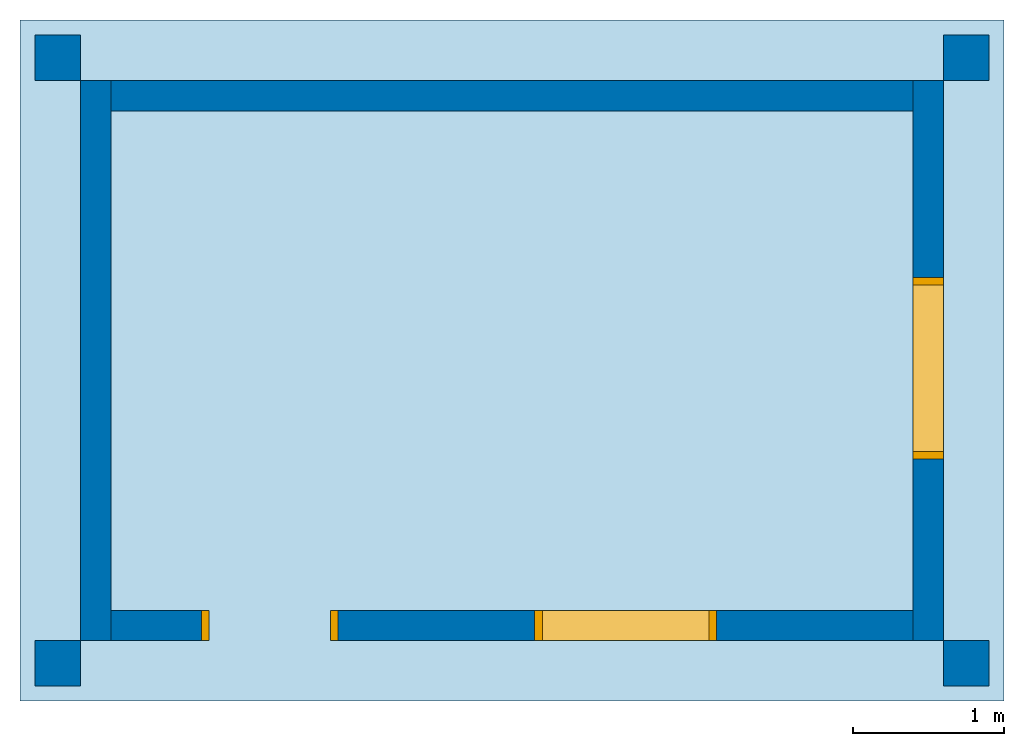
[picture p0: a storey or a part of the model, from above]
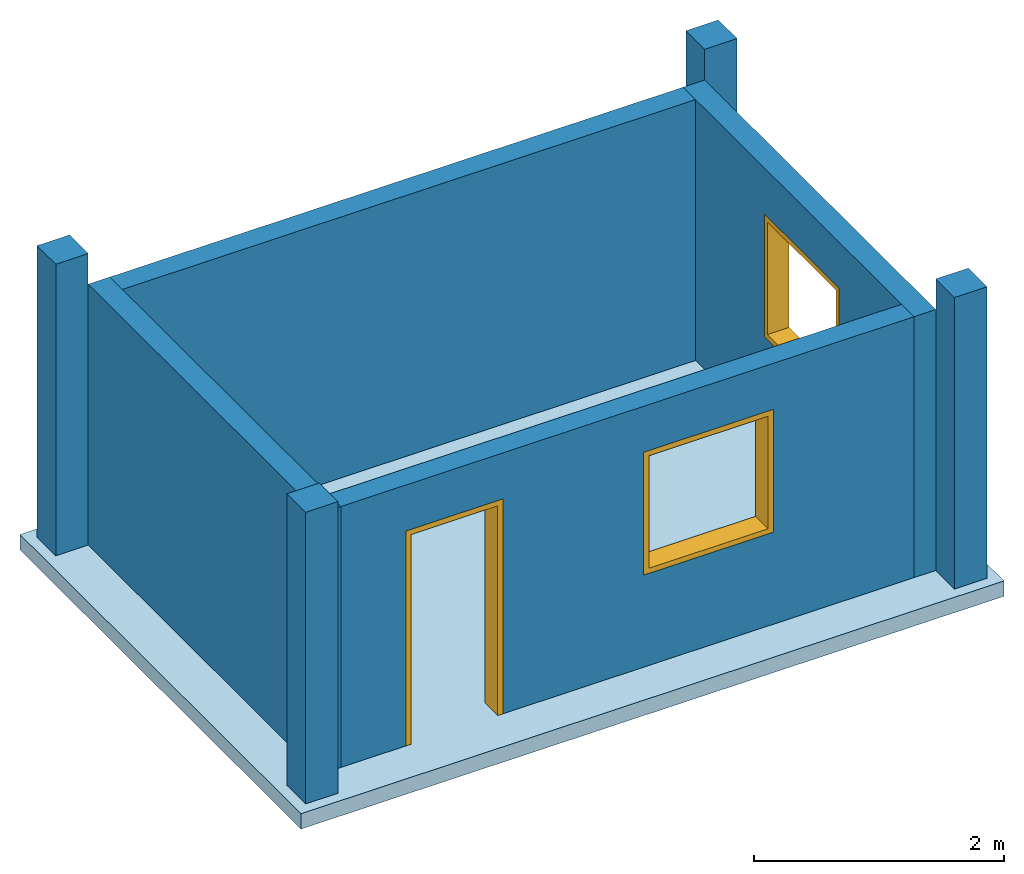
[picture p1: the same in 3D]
Properties of the parts of a building model (IFC4)

# File
Description: 3117 native IFC4 snapshot; declared native building elements and explicit slab-priority joins, Source content revision: b1d7558505e38e8eab14517490e580a875eba1bb7b5503b72d140c259384c804
Time: 2026-10-23T02:40:40
Author: 3117 BIM
Written by: IfcOpenShell 0.8.4
Made in: 3117 BIM Studio 0.5.0

# IfcProject, 3117 อาคารสองชั้น
LongName: BLD-030
BIM3117_Source - ContentRevision: b1d7558505e38e8eab14517490e580a875eba1bb7b5503b72d140c259384c804; NativeObjectName: BIM3117_Project; SourceModel: FreeCAD Document / FCStd; WorkbenchVersion: 0.5.0; ProjectNumber: BLD-030; Author: 3117 BIM; RevisionMeaning: SHA-256 content identity; Undo may restore an earlier identity; QuantityRule: Straight uniform walls, one side; openings deducted; wall joins excluded; CoverageComplete: no

# IfcSite, 3117 Site
BIM3117_Source - ContentRevision: b1d7558505e38e8eab14517490e580a875eba1bb7b5503b72d140c259384c804; Mapping: Generated local site container; no survey/georeferencing claimed

# IfcBuilding, 3117 อาคารสองชั้น
BIM3117_Source - ContentRevision: b1d7558505e38e8eab14517490e580a875eba1bb7b5503b72d140c259384c804; Mapping: Generated building container for the single native Project

# IfcBuildingStorey (3)
In: 3117 อาคารสองชั้น
BIM3117_Source - ContentRevision: b1d7558505e38e8eab14517490e580a875eba1bb7b5503b72d140c259384c804; SourceModel: FreeCAD Document / FCStd; WorkbenchVersion: 0.5.0
Name | Elevation (m) | NativeObjectName
L02 | 6 | BIM3117_Level002
L01 | 3 | BIM3117_Level001
L00 | 0 | BIM3117_Level

# IfcBeam: Beam 300 x 450 (8)
Type - PredefinedType: BEAM; Material: Concrete
Type - BIM3117_Source - ContentRevision: b1d7558505e38e8eab14517490e580a875eba1bb7b5503b72d140c259384c804; NativeObjectName: BIM3117_ElementType002; SourceModel: FreeCAD Document / FCStd; WorkbenchVersion: 0.5.0; TypeCode: B300450; Category: Beam; MaterialLayers: []; WidthM: 0.3; DepthM: 0.45
BIM3117_Source - MaterialDescription: Concrete; JoinRule: Slab takes priority; subtract slab solids from this member only; OffsetM: 0
Qto_BeamBaseQuantities - CrossSectionArea: 0.135 m2
BIM3117_MaterialSource - ContentRevision: b1d7558505e38e8eab14517490e580a875eba1bb7b5503b72d140c259384c804; QuantityRule: 3117.material.native-solid-partition.v1
Name | In | NativeObjectName | JoinDeductionM3 = HomogeneousDeductionVolume (m3) | TopZM | GrossVolume (m3) = HomogeneousGrossVolume (m3) | NetVolume (m3) = HomogeneousNetVolume (m3) | Length (m) | Rows
B12 | L01 | BIM3117_Beam001 | 0.18 | 3 | 0.54 | 0.36 | 4 | [{"category":"Beam","content_revision":"b1d7558505e38e8eab14517490e580a875eba1bb7b5503b72d140c259384c804","deduction_rule":"slab-priority joins","deduction_volume_m3":0.18000000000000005,"element_id":"06e74d45-1fd5-431b-89b8-6fac21c4a78d","gross_volume_m3":0.54,"layer_index":0,"layer_role":"homogeneous","level":"L01","level_id":"3087830e-4d1a-4f80-b674-777b13466c13","material_code":"CONC","material_id":"c914a542-3e86-48de-8977-109cd4dfb8d9","material_name":"Concrete","name":"B12","net_volume_m3":0.36,"object_name":"BIM3117_Beam001","quantity_rule":"3117.material.native-solid-partition.v1","thickness_m":"","type_id":"7873a6d0-4f02-4dc2-a0b7-e65b0801dee5","type_name":"Beam 300 x 450"}]
B21 | L02 | BIM3117_Beam004 | 0.27 | 6 | 0.81 | 0.54 | 6 | [{"category":"Beam","content_revision":"b1d7558505e38e8eab14517490e580a875eba1bb7b5503b72d140c259384c804","deduction_rule":"slab-priority joins","deduction_volume_m3":0.27,"element_id":"0f2f9d10-3b11-4f27-bb93-bc6f454e6b0c","gross_volume_m3":0.81,"layer_index":0,"layer_role":"homogeneous","level":"L02","level_id":"23a017fd-103e-4f8e-bfd1-538f44a944cd","material_code":"CONC","material_id":"c914a542-3e86-48de-8977-109cd4dfb8d9","material_name":"Concrete","name":"B21","net_volume_m3":0.54,"object_name":"BIM3117_Beam004","quantity_rule":"3117.material.native-solid-partition.v1","thickness_m":"","type_id":"7873a6d0-4f02-4dc2-a0b7-e65b0801dee5","type_name":"Beam 300 x 450"}]
B24 | L02 | BIM3117_Beam007 | 0.18 | 6 | 0.54 | 0.36 | 4 | [{"category":"Beam","content_revision":"b1d7558505e38e8eab14517490e580a875eba1bb7b5503b72d140c259384c804","deduction_rule":"slab-priority joins","deduction_volume_m3":0.18000000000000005,"element_id":"37134a20-b003-48ef-96bd-b1457cc94324","gross_volume_m3":0.54,"layer_index":0,"layer_role":"homogeneous","level":"L02","level_id":"23a017fd-103e-4f8e-bfd1-538f44a944cd","material_code":"CONC","material_id":"c914a542-3e86-48de-8977-109cd4dfb8d9","material_name":"Concrete","name":"B24","net_volume_m3":0.36,"object_name":"BIM3117_Beam007","quantity_rule":"3117.material.native-solid-partition.v1","thickness_m":"","type_id":"7873a6d0-4f02-4dc2-a0b7-e65b0801dee5","type_name":"Beam 300 x 450"}]
B11 | L01 | BIM3117_Beam | 0.27 | 3 | 0.81 | 0.54 | 6 | [{"category":"Beam","content_revision":"b1d7558505e38e8eab14517490e580a875eba1bb7b5503b72d140c259384c804","deduction_rule":"slab-priority joins","deduction_volume_m3":0.27,"element_id":"7699609f-dcd3-429b-9ef0-9311904eba1e","gross_volume_m3":0.81,"layer_index":0,"layer_role":"homogeneous","level":"L01","level_id":"3087830e-4d1a-4f80-b674-777b13466c13","material_code":"CONC","material_id":"c914a542-3e86-48de-8977-109cd4dfb8d9","material_name":"Concrete","name":"B11","net_volume_m3":0.54,"object_name":"BIM3117_Beam","quantity_rule":"3117.material.native-solid-partition.v1","thickness_m":"","type_id":"7873a6d0-4f02-4dc2-a0b7-e65b0801dee5","type_name":"Beam 300 x 450"}]
B13 | L01 | BIM3117_Beam002 | 0.27 | 3 | 0.81 | 0.54 | 6 | [{"category":"Beam","content_revision":"b1d7558505e38e8eab14517490e580a875eba1bb7b5503b72d140c259384c804","deduction_rule":"slab-priority joins","deduction_volume_m3":0.27,"element_id":"8a72afa4-2376-45d5-b54b-95efe545bce8","gross_volume_m3":0.81,"layer_index":0,"layer_role":"homogeneous","level":"L01","level_id":"3087830e-4d1a-4f80-b674-777b13466c13","material_code":"CONC","material_id":"c914a542-3e86-48de-8977-109cd4dfb8d9","material_name":"Concrete","name":"B13","net_volume_m3":0.54,"object_name":"BIM3117_Beam002","quantity_rule":"3117.material.native-solid-partition.v1","thickness_m":"","type_id":"7873a6d0-4f02-4dc2-a0b7-e65b0801dee5","type_name":"Beam 300 x 450"}]
B14 | L01 | BIM3117_Beam003 | 0.18 | 3 | 0.54 | 0.36 | 4 | [{"category":"Beam","content_revision":"b1d7558505e38e8eab14517490e580a875eba1bb7b5503b72d140c259384c804","deduction_rule":"slab-priority joins","deduction_volume_m3":0.18000000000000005,"element_id":"c6ba7cea-aaaf-4add-860f-5ea5c8d3f5b0","gross_volume_m3":0.54,"layer_index":0,"layer_role":"homogeneous","level":"L01","level_id":"3087830e-4d1a-4f80-b674-777b13466c13","material_code":"CONC","material_id":"c914a542-3e86-48de-8977-109cd4dfb8d9","material_name":"Concrete","name":"B14","net_volume_m3":0.36,"object_name":"BIM3117_Beam003","quantity_rule":"3117.material.native-solid-partition.v1","thickness_m":"","type_id":"7873a6d0-4f02-4dc2-a0b7-e65b0801dee5","type_name":"Beam 300 x 450"}]
B23 | L02 | BIM3117_Beam006 | 0.27 | 6 | 0.81 | 0.54 | 6 | [{"category":"Beam","content_revision":"b1d7558505e38e8eab14517490e580a875eba1bb7b5503b72d140c259384c804","deduction_rule":"slab-priority joins","deduction_volume_m3":0.27,"element_id":"cfe18d69-5269-46c5-8660-3133d80e9a81","gross_volume_m3":0.81,"layer_index":0,"layer_role":"homogeneous","level":"L02","level_id":"23a017fd-103e-4f8e-bfd1-538f44a944cd","material_code":"CONC","material_id":"c914a542-3e86-48de-8977-109cd4dfb8d9","material_name":"Concrete","name":"B23","net_volume_m3":0.54,"object_name":"BIM3117_Beam006","quantity_rule":"3117.material.native-solid-partition.v1","thickness_m":"","type_id":"7873a6d0-4f02-4dc2-a0b7-e65b0801dee5","type_name":"Beam 300 x 450"}]
B22 | L02 | BIM3117_Beam005 | 0.18 | 6 | 0.54 | 0.36 | 4 | [{"category":"Beam","content_revision":"b1d7558505e38e8eab14517490e580a875eba1bb7b5503b72d140c259384c804","deduction_rule":"slab-priority joins","deduction_volume_m3":0.18000000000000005,"element_id":"fcf4cda7-9e30-4ccb-a21f-6e7e082487e8","gross_volume_m3":0.54,"layer_index":0,"layer_role":"homogeneous","level":"L02","level_id":"23a017fd-103e-4f8e-bfd1-538f44a944cd","material_code":"CONC","material_id":"c914a542-3e86-48de-8977-109cd4dfb8d9","material_name":"Concrete","name":"B22","net_volume_m3":0.36,"object_name":"BIM3117_Beam005","quantity_rule":"3117.material.native-solid-partition.v1","thickness_m":"","type_id":"7873a6d0-4f02-4dc2-a0b7-e65b0801dee5","type_name":"Beam 300 x 450"}]

# IfcColumn: Column 300 x 300 (8)
Type - PredefinedType: COLUMN; Material: Concrete
Type - BIM3117_Source - ContentRevision: b1d7558505e38e8eab14517490e580a875eba1bb7b5503b72d140c259384c804; NativeObjectName: BIM3117_ElementType001; SourceModel: FreeCAD Document / FCStd; WorkbenchVersion: 0.5.0; TypeCode: C300; Category: Column; MaterialLayers: []; WidthM: 0.3; DepthM: 0.3
BIM3117_Source - MaterialDescription: Concrete; JoinDeductionM3: 0.0135; JoinRule: Slab takes priority; subtract slab solids from this member only; BaseOffsetM: 0; TopOffsetM: 0; RotationDegrees: 0
Qto_ColumnBaseQuantities - GrossVolume: 0.27 m3; NetVolume: 0.2565 m3; Length: 3 m; CrossSectionArea: 0.09 m2
BIM3117_MaterialQuantities - HomogeneousGrossVolume: 0.27 m3; HomogeneousDeductionVolume: 0.0135 m3; HomogeneousNetVolume: 0.2565 m3
BIM3117_MaterialSource - ContentRevision: b1d7558505e38e8eab14517490e580a875eba1bb7b5503b72d140c259384c804; QuantityRule: 3117.material.native-solid-partition.v1
Name | In | NativeObjectName | Rows
C13 | L00 | BIM3117_Column002 | [{"category":"Column","content_revision":"b1d7558505e38e8eab14517490e580a875eba1bb7b5503b72d140c259384c804","deduction_rule":"slab-priority joins","deduction_volume_m3":0.013500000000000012,"element_id":"16e87910-40d7-4547-b9d9-ff1431a1c066","gross_volume_m3":0.27,"layer_index":0,"layer_role":"homogeneous","level":"L00","level_id":"4bd6b473-7294-4b93-b953-97c20a2378cf","material_code":"CONC","material_id":"c914a542-3e86-48de-8977-109cd4dfb8d9","material_name":"Concrete","name":"C13","net_volume_m3":0.2565,"object_name":"BIM3117_Column002","quantity_rule":"3117.material.native-solid-partition.v1","thickness_m":"","type_id":"b4f5f8ca-2cbe-4998-ae5e-196581cba6d6","type_name":"Column 300 x 300"}]
C11 | L00 | BIM3117_Column | [{"category":"Column","content_revision":"b1d7558505e38e8eab14517490e580a875eba1bb7b5503b72d140c259384c804","deduction_rule":"slab-priority joins","deduction_volume_m3":0.013500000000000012,"element_id":"3bdc20dc-74ff-49c2-89d3-14a7ef12c5ba","gross_volume_m3":0.27,"layer_index":0,"layer_role":"homogeneous","level":"L00","level_id":"4bd6b473-7294-4b93-b953-97c20a2378cf","material_code":"CONC","material_id":"c914a542-3e86-48de-8977-109cd4dfb8d9","material_name":"Concrete","name":"C11","net_volume_m3":0.2565,"object_name":"BIM3117_Column","quantity_rule":"3117.material.native-solid-partition.v1","thickness_m":"","type_id":"b4f5f8ca-2cbe-4998-ae5e-196581cba6d6","type_name":"Column 300 x 300"}]
C23 | L01 | BIM3117_Column006 | [{"category":"Column","content_revision":"b1d7558505e38e8eab14517490e580a875eba1bb7b5503b72d140c259384c804","deduction_rule":"slab-priority joins","deduction_volume_m3":0.013500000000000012,"element_id":"5da805dc-1e32-4533-9fea-d355df30851d","gross_volume_m3":0.27,"layer_index":0,"layer_role":"homogeneous","level":"L01","level_id":"3087830e-4d1a-4f80-b674-777b13466c13","material_code":"CONC","material_id":"c914a542-3e86-48de-8977-109cd4dfb8d9","material_name":"Concrete","name":"C23","net_volume_m3":0.2565,"object_name":"BIM3117_Column006","quantity_rule":"3117.material.native-solid-partition.v1","thickness_m":"","type_id":"b4f5f8ca-2cbe-4998-ae5e-196581cba6d6","type_name":"Column 300 x 300"}]
C14 | L00 | BIM3117_Column003 | [{"category":"Column","content_revision":"b1d7558505e38e8eab14517490e580a875eba1bb7b5503b72d140c259384c804","deduction_rule":"slab-priority joins","deduction_volume_m3":0.013500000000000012,"element_id":"8af0d977-4367-4d13-8ec3-0f9190dd8d12","gross_volume_m3":0.27,"layer_index":0,"layer_role":"homogeneous","level":"L00","level_id":"4bd6b473-7294-4b93-b953-97c20a2378cf","material_code":"CONC","material_id":"c914a542-3e86-48de-8977-109cd4dfb8d9","material_name":"Concrete","name":"C14","net_volume_m3":0.2565,"object_name":"BIM3117_Column003","quantity_rule":"3117.material.native-solid-partition.v1","thickness_m":"","type_id":"b4f5f8ca-2cbe-4998-ae5e-196581cba6d6","type_name":"Column 300 x 300"}]
C22 | L01 | BIM3117_Column005 | [{"category":"Column","content_revision":"b1d7558505e38e8eab14517490e580a875eba1bb7b5503b72d140c259384c804","deduction_rule":"slab-priority joins","deduction_volume_m3":0.013500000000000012,"element_id":"9b08ba70-d0e3-4818-93b4-765960d3b282","gross_volume_m3":0.27,"layer_index":0,"layer_role":"homogeneous","level":"L01","level_id":"3087830e-4d1a-4f80-b674-777b13466c13","material_code":"CONC","material_id":"c914a542-3e86-48de-8977-109cd4dfb8d9","material_name":"Concrete","name":"C22","net_volume_m3":0.2565,"object_name":"BIM3117_Column005","quantity_rule":"3117.material.native-solid-partition.v1","thickness_m":"","type_id":"b4f5f8ca-2cbe-4998-ae5e-196581cba6d6","type_name":"Column 300 x 300"}]
C24 | L01 | BIM3117_Column007 | [{"category":"Column","content_revision":"b1d7558505e38e8eab14517490e580a875eba1bb7b5503b72d140c259384c804","deduction_rule":"slab-priority joins","deduction_volume_m3":0.013500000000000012,"element_id":"9f427961-e1b5-4ae5-ab86-dfa4fd093a51","gross_volume_m3":0.27,"layer_index":0,"layer_role":"homogeneous","level":"L01","level_id":"3087830e-4d1a-4f80-b674-777b13466c13","material_code":"CONC","material_id":"c914a542-3e86-48de-8977-109cd4dfb8d9","material_name":"Concrete","name":"C24","net_volume_m3":0.2565,"object_name":"BIM3117_Column007","quantity_rule":"3117.material.native-solid-partition.v1","thickness_m":"","type_id":"b4f5f8ca-2cbe-4998-ae5e-196581cba6d6","type_name":"Column 300 x 300"}]
C21 | L01 | BIM3117_Column004 | [{"category":"Column","content_revision":"b1d7558505e38e8eab14517490e580a875eba1bb7b5503b72d140c259384c804","deduction_rule":"slab-priority joins","deduction_volume_m3":0.013500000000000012,"element_id":"a444a497-4a42-4a02-805f-bdac76a1312e","gross_volume_m3":0.27,"layer_index":0,"layer_role":"homogeneous","level":"L01","level_id":"3087830e-4d1a-4f80-b674-777b13466c13","material_code":"CONC","material_id":"c914a542-3e86-48de-8977-109cd4dfb8d9","material_name":"Concrete","name":"C21","net_volume_m3":0.2565,"object_name":"BIM3117_Column004","quantity_rule":"3117.material.native-solid-partition.v1","thickness_m":"","type_id":"b4f5f8ca-2cbe-4998-ae5e-196581cba6d6","type_name":"Column 300 x 300"}]
C12 | L00 | BIM3117_Column001 | [{"category":"Column","content_revision":"b1d7558505e38e8eab14517490e580a875eba1bb7b5503b72d140c259384c804","deduction_rule":"slab-priority joins","deduction_volume_m3":0.013500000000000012,"element_id":"c6881a57-0739-4382-9db8-b187e4745510","gross_volume_m3":0.27,"layer_index":0,"layer_role":"homogeneous","level":"L00","level_id":"4bd6b473-7294-4b93-b953-97c20a2378cf","material_code":"CONC","material_id":"c914a542-3e86-48de-8977-109cd4dfb8d9","material_name":"Concrete","name":"C12","net_volume_m3":0.2565,"object_name":"BIM3117_Column001","quantity_rule":"3117.material.native-solid-partition.v1","thickness_m":"","type_id":"b4f5f8ca-2cbe-4998-ae5e-196581cba6d6","type_name":"Column 300 x 300"}]

# IfcDoor: Door 900 x 2100 (2)
Type - PredefinedType: DOOR; ParameterTakesPrecedence: no; Material: Timber frame
Type - BIM3117_Source - ContentRevision: b1d7558505e38e8eab14517490e580a875eba1bb7b5503b72d140c259384c804; NativeObjectName: BIM3117_ElementType003; SourceModel: FreeCAD Document / FCStd; WorkbenchVersion: 0.5.0; TypeCode: D09021; Category: Door; MaterialLayers: []; WidthM: 0.9; HeightM: 2.1; DimensionMeaning: Overall wall-cut opening including generic frame; no leaf, glazing or clear passage specification
OverallHeight: 2.1 m; OverallWidth: 0.9 m
BIM3117_Source - OffsetM: 0.8; SillM: 0; Geometry: Generic three-bar frame, no leaf/handing/swing; DimensionMeaning: Overall wall-cut opening including frame; not clear passage or leaf; FrameVolumeM3: 0.05
BIM3117_MaterialQuantities - HomogeneousGrossVolume: 0.05 m3; HomogeneousDeductionVolume: 0 m3; HomogeneousNetVolume: 0.05 m3
BIM3117_MaterialSource - ContentRevision: b1d7558505e38e8eab14517490e580a875eba1bb7b5503b72d140c259384c804; QuantityRule: 3117.material.native-solid-partition.v1
Name | In | NativeObjectName | Rows
D01 | L00 | BIM3117_Door | [{"category":"Door","content_revision":"b1d7558505e38e8eab14517490e580a875eba1bb7b5503b72d140c259384c804","deduction_rule":"none; generic frame solid, not the wall opening","deduction_volume_m3":0.0,"element_id":"1fa369d5-9536-4c2e-9a15-ad3f3c55335d","gross_volume_m3":0.05000000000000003,"layer_index":0,"layer_role":"homogeneous","level":"L00","level_id":"4bd6b473-7294-4b93-b953-97c20a2378cf","material_code":"TIMBER","material_id":"76dc9624-8ca1-4adf-bedd-d0c6d80f101f","material_name":"Timber frame","name":"D01","net_volume_m3":0.05000000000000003,"object_name":"BIM3117_Door","quantity_rule":"3117.material.native-solid-partition.v1","thickness_m":"","type_id":"beb26577-e19f-4adb-a358-948dab5f1c70","type_name":"Door 900 x 2100"}]
D02 | L01 | BIM3117_Door001 | [{"category":"Door","content_revision":"b1d7558505e38e8eab14517490e580a875eba1bb7b5503b72d140c259384c804","deduction_rule":"none; generic frame solid, not the wall opening","deduction_volume_m3":0.0,"element_id":"72e4552c-3f40-4e11-aa22-a893e213a28e","gross_volume_m3":0.05000000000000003,"layer_index":0,"layer_role":"homogeneous","level":"L01","level_id":"3087830e-4d1a-4f80-b674-777b13466c13","material_code":"TIMBER","material_id":"76dc9624-8ca1-4adf-bedd-d0c6d80f101f","material_name":"Timber frame","name":"D02","net_volume_m3":0.05000000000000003,"object_name":"BIM3117_Door001","quantity_rule":"3117.material.native-solid-partition.v1","thickness_m":"","type_id":"beb26577-e19f-4adb-a358-948dab5f1c70","type_name":"Door 900 x 2100"}]

# IfcOpeningElement (6)
PredefinedType: OPENING
BIM3117_Source - ContentRevision: b1d7558505e38e8eab14517490e580a875eba1bb7b5503b72d140c259384c804; BooleanPaddingM: 0.000001
Name | In
Opening — WIN22 | L01
Opening — D01 | L00
Opening — WIN21 | L01
Opening — D02 | L01
Opening — WIN12 | L00
Opening — WIN11 | L00

# IfcSlab: Slab 150 layered (3)
Type - PredefinedType: FLOOR; Material: Floor finish 0.01 m, Screed 0.04 m, Concrete 0.1 m
Type - BIM3117_Source - ContentRevision: b1d7558505e38e8eab14517490e580a875eba1bb7b5503b72d140c259384c804; NativeObjectName: BIM3117_ElementType; SourceModel: FreeCAD Document / FCStd; WorkbenchVersion: 0.5.0; TypeCode: S150; Category: Slab; MaterialLayers: [{"material_id":"0ae0a897-4649-4874-8093-5bfe9567f215","role":"finish","thickness_m":0.01},{"material_id":"0e4bf164-d1c0-429a-9c15-62911cfd8f3c","role":"substrate","thickness_m":0.04},{"material_id":"c914a542-3e86-48de-8977-109cd4dfb8d9","role":"structure","thickness_m":0.1}]; ThicknessM: 0.15
BIM3117_Source - MaterialDescription: Floor finish / Screed / Concrete; JoinDeductionM3: 0; JoinRule: No explicit joins; OffsetM: 0
Qto_SlabBaseQuantities - GrossVolume: 4.3875 m3; NetVolume: 4.3875 m3; Depth: 0.15 m; Perimeter: 22 m; GrossArea: 29.25 m2; NetArea: 29.25 m2
BIM3117_MaterialQuantities - Layer1GrossVolume: 0.2925 m3; Layer1DeductionVolume: 0 m3; Layer1NetVolume: 0.2925 m3; Layer2GrossVolume: 1.17 m3; Layer2DeductionVolume: 0 m3; Layer2NetVolume: 1.17 m3; Layer3GrossVolume: 2.925 m3; Layer3DeductionVolume: 0 m3; Layer3NetVolume: 2.925 m3
BIM3117_MaterialSource - ContentRevision: b1d7558505e38e8eab14517490e580a875eba1bb7b5503b72d140c259384c804; QuantityRule: 3117.material.native-solid-partition.v1
Name | In | NativeObjectName | TopZM | Rows
S00 | L00 | BIM3117_Slab | 0 | [{"category":"Slab","content_revision":"b1d7558505e38e8eab14517490e580a875eba1bb7b5503b72d140c259384c804","deduction_rule":"none","deduction_volume_m3":0.0,"element_id":"12aaaac7-9205-4f0b-942f-ac329d10ab85","gross_volume_m3":0.2925,"layer_index":1,"layer_role":"finish","level":"L00","level_id":"4bd6b473-7294-4b93-b953-97c20a2378cf","material_code":"FINISH","material_id":"0ae0a897-4649-4874-8093-5bfe9567f215","material_name":"Floor finish","name":"S00","net_volume_m3":0.2925,"object_name":"BIM3117_Slab","quantity_rule":"3117.material.native-solid-partition.v1","thickness_m":0.01,"type_id":"f2ef2392-a9c0-45fd-93f5-498b684748f0","type_name":"Slab 150 layered"},{"category":"Slab","content_revision":"b1d7558505e38e8eab14517490e580a875eba1bb7b5503b72d140c259384c804","deduction_rule":"none","deduction_volume_m3":0.0,"element_id":"12aaaac7-9205-4f0b-942f-ac329d10ab85","gross_volume_m3":1.17,"layer_index":2,"layer_role":"substrate","level":"L00","level_id":"4bd6b473-7294-4b93-b953-97c20a2378cf","material_code":"SCREED","material_id":"0e4bf164-d1c0-429a-9c15-62911cfd8f3c","material_name":"Screed","name":"S00","net_volume_m3":1.17,"object_name":"BIM3117_Slab","quantity_rule":"3117.material.native-solid-partition.v1","thickness_m":0.04,"type_id":"f2ef2392-a9c0-45fd-93f5-498b684748f0","type_name":"Slab 150 layered"},{"category":"Slab","content_revision":"b1d7558505e38e8eab14517490e580a875eba1bb7b5503b72d140c259384c804","deduction_rule":"none","deduction_volume_m3":0.0,"element_id":"12aaaac7-9205-4f0b-942f-ac329d10ab85","gross_volume_m3":2.925,"layer_index":3,"layer_role":"structure","level":"L00","level_id":"4bd6b473-7294-4b93-b953-97c20a2378cf","material_code":"CONC","material_id":"c914a542-3e86-48de-8977-109cd4dfb8d9","material_name":"Concrete","name":"S00","net_volume_m3":2.925,"object_name":"BIM3117_Slab","quantity_rule":"3117.material.native-solid-partition.v1","thickness_m":0.1,"type_id":"f2ef2392-a9c0-45fd-93f5-498b684748f0","type_name":"Slab 150 layered"}]
S01 | L01 | BIM3117_Slab001 | 3 | [{"category":"Slab","content_revision":"b1d7558505e38e8eab14517490e580a875eba1bb7b5503b72d140c259384c804","deduction_rule":"none","deduction_volume_m3":0.0,"element_id":"54a5fde8-157c-40b7-be56-f69869705b43","gross_volume_m3":0.2925,"layer_index":1,"layer_role":"finish","level":"L01","level_id":"3087830e-4d1a-4f80-b674-777b13466c13","material_code":"FINISH","material_id":"0ae0a897-4649-4874-8093-5bfe9567f215","material_name":"Floor finish","name":"S01","net_volume_m3":0.2925,"object_name":"BIM3117_Slab001","quantity_rule":"3117.material.native-solid-partition.v1","thickness_m":0.01,"type_id":"f2ef2392-a9c0-45fd-93f5-498b684748f0","type_name":"Slab 150 layered"},{"category":"Slab","content_revision":"b1d7558505e38e8eab14517490e580a875eba1bb7b5503b72d140c259384c804","deduction_rule":"none","deduction_volume_m3":0.0,"element_id":"54a5fde8-157c-40b7-be56-f69869705b43","gross_volume_m3":1.17,"layer_index":2,"layer_role":"substrate","level":"L01","level_id":"3087830e-4d1a-4f80-b674-777b13466c13","material_code":"SCREED","material_id":"0e4bf164-d1c0-429a-9c15-62911cfd8f3c","material_name":"Screed","name":"S01","net_volume_m3":1.17,"object_name":"BIM3117_Slab001","quantity_rule":"3117.material.native-solid-partition.v1","thickness_m":0.04,"type_id":"f2ef2392-a9c0-45fd-93f5-498b684748f0","type_name":"Slab 150 layered"},{"category":"Slab","content_revision":"b1d7558505e38e8eab14517490e580a875eba1bb7b5503b72d140c259384c804","deduction_rule":"none","deduction_volume_m3":0.0,"element_id":"54a5fde8-157c-40b7-be56-f69869705b43","gross_volume_m3":2.925,"layer_index":3,"layer_role":"structure","level":"L01","level_id":"3087830e-4d1a-4f80-b674-777b13466c13","material_code":"CONC","material_id":"c914a542-3e86-48de-8977-109cd4dfb8d9","material_name":"Concrete","name":"S01","net_volume_m3":2.925,"object_name":"BIM3117_Slab001","quantity_rule":"3117.material.native-solid-partition.v1","thickness_m":0.1,"type_id":"f2ef2392-a9c0-45fd-93f5-498b684748f0","type_name":"Slab 150 layered"}]
S02 | L02 | BIM3117_Slab002 | 6 | [{"category":"Slab","content_revision":"b1d7558505e38e8eab14517490e580a875eba1bb7b5503b72d140c259384c804","deduction_rule":"none","deduction_volume_m3":0.0,"element_id":"e766c1c9-f102-490f-88fa-979e8089bb06","gross_volume_m3":0.2925,"layer_index":1,"layer_role":"finish","level":"L02","level_id":"23a017fd-103e-4f8e-bfd1-538f44a944cd","material_code":"FINISH","material_id":"0ae0a897-4649-4874-8093-5bfe9567f215","material_name":"Floor finish","name":"S02","net_volume_m3":0.2925,"object_name":"BIM3117_Slab002","quantity_rule":"3117.material.native-solid-partition.v1","thickness_m":0.01,"type_id":"f2ef2392-a9c0-45fd-93f5-498b684748f0","type_name":"Slab 150 layered"},{"category":"Slab","content_revision":"b1d7558505e38e8eab14517490e580a875eba1bb7b5503b72d140c259384c804","deduction_rule":"none","deduction_volume_m3":0.0,"element_id":"e766c1c9-f102-490f-88fa-979e8089bb06","gross_volume_m3":1.17,"layer_index":2,"layer_role":"substrate","level":"L02","level_id":"23a017fd-103e-4f8e-bfd1-538f44a944cd","material_code":"SCREED","material_id":"0e4bf164-d1c0-429a-9c15-62911cfd8f3c","material_name":"Screed","name":"S02","net_volume_m3":1.17,"object_name":"BIM3117_Slab002","quantity_rule":"3117.material.native-solid-partition.v1","thickness_m":0.04,"type_id":"f2ef2392-a9c0-45fd-93f5-498b684748f0","type_name":"Slab 150 layered"},{"category":"Slab","content_revision":"b1d7558505e38e8eab14517490e580a875eba1bb7b5503b72d140c259384c804","deduction_rule":"none","deduction_volume_m3":0.0,"element_id":"e766c1c9-f102-490f-88fa-979e8089bb06","gross_volume_m3":2.925,"layer_index":3,"layer_role":"structure","level":"L02","level_id":"23a017fd-103e-4f8e-bfd1-538f44a944cd","material_code":"CONC","material_id":"c914a542-3e86-48de-8977-109cd4dfb8d9","material_name":"Concrete","name":"S02","net_volume_m3":2.925,"object_name":"BIM3117_Slab002","quantity_rule":"3117.material.native-solid-partition.v1","thickness_m":0.1,"type_id":"f2ef2392-a9c0-45fd-93f5-498b684748f0","type_name":"Slab 150 layered"}]

# IfcWall: Wall 200 layered (8)
Type - PredefinedType: STANDARD; Material: Plaster 0.015 m, Masonry 0.17 m, Plaster 0.015 m
Type - BIM3117_Source - ContentRevision: b1d7558505e38e8eab14517490e580a875eba1bb7b5503b72d140c259384c804; NativeObjectName: BIM3117_WallType; SourceModel: FreeCAD Document / FCStd; WorkbenchVersion: 0.5.0; ThicknessM: 0.2; MaterialDescription: Plaster / Masonry / Plaster; Assembly: Ordered native material layers along local +Y; TypeCode: W200; Category: Wall; MaterialLayers: [{"material_id":"52f257eb-2c99-4630-9ba8-4108f966e817","role":"finish","thickness_m":0.015},{"material_id":"09ac0651-dd5b-492a-845e-e1a702f0de0b","role":"core","thickness_m":0.17},{"material_id":"52f257eb-2c99-4630-9ba8-4108f966e817","role":"finish","thickness_m":0.015}]
BIM3117_Source - BaseOffsetM: 0; TopOffsetM: -0.45; QuantityRule: One wall, one side; actual cut solid; no wall joins/layers
Qto_WallBaseQuantities - Width: 0.2 m; Height: 2.55 m
BIM3117_MaterialSource - ContentRevision: b1d7558505e38e8eab14517490e580a875eba1bb7b5503b72d140c259384c804; QuantityRule: 3117.material.native-solid-partition.v1
Name | In | NativeObjectName | Length (m) | GrossSideArea (m2) | NetSideArea (m2) | GrossVolume (m3) | NetVolume (m3) | Layer1GrossVolume (m3) = Layer3GrossVolume (m3) | Layer1DeductionVolume (m3) = Layer3DeductionVolume (m3) | Layer1NetVolume (m3) = Layer3NetVolume (m3) | Layer2GrossVolume (m3) | Layer2DeductionVolume (m3) | Layer2NetVolume (m3) | Rows
Wall 1-2 | L00 | BIM3117_Wall001 | 3.7 | 9.435 | 7.995 | 1.887 | 1.599 | 0.141525 | 0.0216 | 0.119925 | 1.60395 | 0.2448 | 1.35915 | [{"category":"Wall","content_revision":"b1d7558505e38e8eab14517490e580a875eba1bb7b5503b72d140c259384c804","deduction_rule":"openings","deduction_volume_m3":0.021600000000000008,"element_id":"2dbab9a3-fe47-48df-802e-a98cbe1553d7","gross_volume_m3":0.141525,"layer_index":1,"layer_role":"finish","level":"L00","level_id":"4bd6b473-7294-4b93-b953-97c20a2378cf","material_code":"PLASTER","material_id":"52f257eb-2c99-4630-9ba8-4108f966e817","material_name":"Plaster","name":"Wall 1-2","net_volume_m3":0.119925,"object_name":"BIM3117_Wall001","quantity_rule":"3117.material.native-solid-partition.v1","thickness_m":0.015,"type_id":"65e313b7-786b-475f-994c-60b3af109888","type_name":"Wall 200 layered"},{"category":"Wall","content_revision":"b1d7558505e38e8eab14517490e580a875eba1bb7b5503b72d140c259384c804","deduction_rule":"openings","deduction_volume_m3":0.2447999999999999,"element_id":"2dbab9a3-fe47-48df-802e-a98cbe1553d7","gross_volume_m3":1.60395,"layer_index":2,"layer_role":"core","level":"L00","level_id":"4bd6b473-7294-4b93-b953-97c20a2378cf","material_code":"MASONRY","material_id":"09ac0651-dd5b-492a-845e-e1a702f0de0b","material_name":"Masonry","name":"Wall 1-2","net_volume_m3":1.35915,"object_name":"BIM3117_Wall001","quantity_rule":"3117.material.native-solid-partition.v1","thickness_m":0.17,"type_id":"65e313b7-786b-475f-994c-60b3af109888","type_name":"Wall 200 layered"},{"category":"Wall","content_revision":"b1d7558505e38e8eab14517490e580a875eba1bb7b5503b72d140c259384c804","deduction_rule":"openings","deduction_volume_m3":0.021600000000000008,"element_id":"2dbab9a3-fe47-48df-802e-a98cbe1553d7","gross_volume_m3":0.141525,"layer_index":3,"layer_role":"finish","level":"L00","level_id":"4bd6b473-7294-4b93-b953-97c20a2378cf","material_code":"PLASTER","material_id":"52f257eb-2c99-4630-9ba8-4108f966e817","material_name":"Plaster","name":"Wall 1-2","net_volume_m3":0.119925,"object_name":"BIM3117_Wall001","quantity_rule":"3117.material.native-solid-partition.v1","thickness_m":0.015,"type_id":"65e313b7-786b-475f-994c-60b3af109888","type_name":"Wall 200 layered"}]
Wall 1-1 | L00 | BIM3117_Wall | 5.7 | 14.535 | 11.205 | 2.907 | 2.241 | 0.218025 | 0.04995 | 0.168075 | 2.47095 | 0.5661 | 1.90485 | [{"category":"Wall","content_revision":"b1d7558505e38e8eab14517490e580a875eba1bb7b5503b72d140c259384c804","deduction_rule":"openings","deduction_volume_m3":0.049949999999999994,"element_id":"4594d0f2-e4b6-4eac-b6c6-f0cf3c4ccb4f","gross_volume_m3":0.218025,"layer_index":1,"layer_role":"finish","level":"L00","level_id":"4bd6b473-7294-4b93-b953-97c20a2378cf","material_code":"PLASTER","material_id":"52f257eb-2c99-4630-9ba8-4108f966e817","material_name":"Plaster","name":"Wall 1-1","net_volume_m3":0.168075,"object_name":"BIM3117_Wall","quantity_rule":"3117.material.native-solid-partition.v1","thickness_m":0.015,"type_id":"65e313b7-786b-475f-994c-60b3af109888","type_name":"Wall 200 layered"},{"category":"Wall","content_revision":"b1d7558505e38e8eab14517490e580a875eba1bb7b5503b72d140c259384c804","deduction_rule":"openings","deduction_volume_m3":0.5661000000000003,"element_id":"4594d0f2-e4b6-4eac-b6c6-f0cf3c4ccb4f","gross_volume_m3":2.47095,"layer_index":2,"layer_role":"core","level":"L00","level_id":"4bd6b473-7294-4b93-b953-97c20a2378cf","material_code":"MASONRY","material_id":"09ac0651-dd5b-492a-845e-e1a702f0de0b","material_name":"Masonry","name":"Wall 1-1","net_volume_m3":1.90485,"object_name":"BIM3117_Wall","quantity_rule":"3117.material.native-solid-partition.v1","thickness_m":0.17,"type_id":"65e313b7-786b-475f-994c-60b3af109888","type_name":"Wall 200 layered"},{"category":"Wall","content_revision":"b1d7558505e38e8eab14517490e580a875eba1bb7b5503b72d140c259384c804","deduction_rule":"openings","deduction_volume_m3":0.049949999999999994,"element_id":"4594d0f2-e4b6-4eac-b6c6-f0cf3c4ccb4f","gross_volume_m3":0.218025,"layer_index":3,"layer_role":"finish","level":"L00","level_id":"4bd6b473-7294-4b93-b953-97c20a2378cf","material_code":"PLASTER","material_id":"52f257eb-2c99-4630-9ba8-4108f966e817","material_name":"Plaster","name":"Wall 1-1","net_volume_m3":0.168075,"object_name":"BIM3117_Wall","quantity_rule":"3117.material.native-solid-partition.v1","thickness_m":0.015,"type_id":"65e313b7-786b-475f-994c-60b3af109888","type_name":"Wall 200 layered"}]
Wall 2-1 | L01 | BIM3117_Wall004 | 5.7 | 14.535 | 11.205 | 2.907 | 2.241 | 0.218025 | 0.04995 | 0.168075 | 2.47095 | 0.5661 | 1.90485 | [{"category":"Wall","content_revision":"b1d7558505e38e8eab14517490e580a875eba1bb7b5503b72d140c259384c804","deduction_rule":"openings","deduction_volume_m3":0.049949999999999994,"element_id":"4748dd71-525a-4434-ba86-b7e616563128","gross_volume_m3":0.218025,"layer_index":1,"layer_role":"finish","level":"L01","level_id":"3087830e-4d1a-4f80-b674-777b13466c13","material_code":"PLASTER","material_id":"52f257eb-2c99-4630-9ba8-4108f966e817","material_name":"Plaster","name":"Wall 2-1","net_volume_m3":0.168075,"object_name":"BIM3117_Wall004","quantity_rule":"3117.material.native-solid-partition.v1","thickness_m":0.015,"type_id":"65e313b7-786b-475f-994c-60b3af109888","type_name":"Wall 200 layered"},{"category":"Wall","content_revision":"b1d7558505e38e8eab14517490e580a875eba1bb7b5503b72d140c259384c804","deduction_rule":"openings","deduction_volume_m3":0.5661000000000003,"element_id":"4748dd71-525a-4434-ba86-b7e616563128","gross_volume_m3":2.47095,"layer_index":2,"layer_role":"core","level":"L01","level_id":"3087830e-4d1a-4f80-b674-777b13466c13","material_code":"MASONRY","material_id":"09ac0651-dd5b-492a-845e-e1a702f0de0b","material_name":"Masonry","name":"Wall 2-1","net_volume_m3":1.90485,"object_name":"BIM3117_Wall004","quantity_rule":"3117.material.native-solid-partition.v1","thickness_m":0.17,"type_id":"65e313b7-786b-475f-994c-60b3af109888","type_name":"Wall 200 layered"},{"category":"Wall","content_revision":"b1d7558505e38e8eab14517490e580a875eba1bb7b5503b72d140c259384c804","deduction_rule":"openings","deduction_volume_m3":0.049949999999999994,"element_id":"4748dd71-525a-4434-ba86-b7e616563128","gross_volume_m3":0.218025,"layer_index":3,"layer_role":"finish","level":"L01","level_id":"3087830e-4d1a-4f80-b674-777b13466c13","material_code":"PLASTER","material_id":"52f257eb-2c99-4630-9ba8-4108f966e817","material_name":"Plaster","name":"Wall 2-1","net_volume_m3":0.168075,"object_name":"BIM3117_Wall004","quantity_rule":"3117.material.native-solid-partition.v1","thickness_m":0.015,"type_id":"65e313b7-786b-475f-994c-60b3af109888","type_name":"Wall 200 layered"}]
Wall 2-2 | L01 | BIM3117_Wall005 | 3.7 | 9.435 | 7.995 | 1.887 | 1.599 | 0.141525 | 0.0216 | 0.119925 | 1.60395 | 0.2448 | 1.35915 | [{"category":"Wall","content_revision":"b1d7558505e38e8eab14517490e580a875eba1bb7b5503b72d140c259384c804","deduction_rule":"openings","deduction_volume_m3":0.021600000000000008,"element_id":"665ad71a-4ce2-454b-a84a-154125035cd7","gross_volume_m3":0.141525,"layer_index":1,"layer_role":"finish","level":"L01","level_id":"3087830e-4d1a-4f80-b674-777b13466c13","material_code":"PLASTER","material_id":"52f257eb-2c99-4630-9ba8-4108f966e817","material_name":"Plaster","name":"Wall 2-2","net_volume_m3":0.119925,"object_name":"BIM3117_Wall005","quantity_rule":"3117.material.native-solid-partition.v1","thickness_m":0.015,"type_id":"65e313b7-786b-475f-994c-60b3af109888","type_name":"Wall 200 layered"},{"category":"Wall","content_revision":"b1d7558505e38e8eab14517490e580a875eba1bb7b5503b72d140c259384c804","deduction_rule":"openings","deduction_volume_m3":0.2447999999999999,"element_id":"665ad71a-4ce2-454b-a84a-154125035cd7","gross_volume_m3":1.60395,"layer_index":2,"layer_role":"core","level":"L01","level_id":"3087830e-4d1a-4f80-b674-777b13466c13","material_code":"MASONRY","material_id":"09ac0651-dd5b-492a-845e-e1a702f0de0b","material_name":"Masonry","name":"Wall 2-2","net_volume_m3":1.35915,"object_name":"BIM3117_Wall005","quantity_rule":"3117.material.native-solid-partition.v1","thickness_m":0.17,"type_id":"65e313b7-786b-475f-994c-60b3af109888","type_name":"Wall 200 layered"},{"category":"Wall","content_revision":"b1d7558505e38e8eab14517490e580a875eba1bb7b5503b72d140c259384c804","deduction_rule":"openings","deduction_volume_m3":0.021600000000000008,"element_id":"665ad71a-4ce2-454b-a84a-154125035cd7","gross_volume_m3":0.141525,"layer_index":3,"layer_role":"finish","level":"L01","level_id":"3087830e-4d1a-4f80-b674-777b13466c13","material_code":"PLASTER","material_id":"52f257eb-2c99-4630-9ba8-4108f966e817","material_name":"Plaster","name":"Wall 2-2","net_volume_m3":0.119925,"object_name":"BIM3117_Wall005","quantity_rule":"3117.material.native-solid-partition.v1","thickness_m":0.015,"type_id":"65e313b7-786b-475f-994c-60b3af109888","type_name":"Wall 200 layered"}]
Wall 2-3 | L01 | BIM3117_Wall006 | 5.7 | 14.535 | 14.535 | 2.907 | 2.907 | 0.218025 | 0 | 0.218025 | 2.47095 | 0 | 2.47095 | [{"category":"Wall","content_revision":"b1d7558505e38e8eab14517490e580a875eba1bb7b5503b72d140c259384c804","deduction_rule":"openings","deduction_volume_m3":0.0,"element_id":"ad010079-9d0f-417e-8859-e6e3f9f6b248","gross_volume_m3":0.218025,"layer_index":1,"layer_role":"finish","level":"L01","level_id":"3087830e-4d1a-4f80-b674-777b13466c13","material_code":"PLASTER","material_id":"52f257eb-2c99-4630-9ba8-4108f966e817","material_name":"Plaster","name":"Wall 2-3","net_volume_m3":0.218025,"object_name":"BIM3117_Wall006","quantity_rule":"3117.material.native-solid-partition.v1","thickness_m":0.015,"type_id":"65e313b7-786b-475f-994c-60b3af109888","type_name":"Wall 200 layered"},{"category":"Wall","content_revision":"b1d7558505e38e8eab14517490e580a875eba1bb7b5503b72d140c259384c804","deduction_rule":"openings","deduction_volume_m3":0.0,"element_id":"ad010079-9d0f-417e-8859-e6e3f9f6b248","gross_volume_m3":2.47095,"layer_index":2,"layer_role":"core","level":"L01","level_id":"3087830e-4d1a-4f80-b674-777b13466c13","material_code":"MASONRY","material_id":"09ac0651-dd5b-492a-845e-e1a702f0de0b","material_name":"Masonry","name":"Wall 2-3","net_volume_m3":2.47095,"object_name":"BIM3117_Wall006","quantity_rule":"3117.material.native-solid-partition.v1","thickness_m":0.17,"type_id":"65e313b7-786b-475f-994c-60b3af109888","type_name":"Wall 200 layered"},{"category":"Wall","content_revision":"b1d7558505e38e8eab14517490e580a875eba1bb7b5503b72d140c259384c804","deduction_rule":"openings","deduction_volume_m3":0.0,"element_id":"ad010079-9d0f-417e-8859-e6e3f9f6b248","gross_volume_m3":0.218025,"layer_index":3,"layer_role":"finish","level":"L01","level_id":"3087830e-4d1a-4f80-b674-777b13466c13","material_code":"PLASTER","material_id":"52f257eb-2c99-4630-9ba8-4108f966e817","material_name":"Plaster","name":"Wall 2-3","net_volume_m3":0.218025,"object_name":"BIM3117_Wall006","quantity_rule":"3117.material.native-solid-partition.v1","thickness_m":0.015,"type_id":"65e313b7-786b-475f-994c-60b3af109888","type_name":"Wall 200 layered"}]
Wall 1-4 | L00 | BIM3117_Wall003 | 3.7 | 9.435 | 9.435 | 1.887 | 1.887 | 0.141525 | 0 | 0.141525 | 1.60395 | 0 | 1.60395 | [{"category":"Wall","content_revision":"b1d7558505e38e8eab14517490e580a875eba1bb7b5503b72d140c259384c804","deduction_rule":"openings","deduction_volume_m3":0.0,"element_id":"dbf814eb-5b9e-46d8-920e-1708f310fba8","gross_volume_m3":0.141525,"layer_index":1,"layer_role":"finish","level":"L00","level_id":"4bd6b473-7294-4b93-b953-97c20a2378cf","material_code":"PLASTER","material_id":"52f257eb-2c99-4630-9ba8-4108f966e817","material_name":"Plaster","name":"Wall 1-4","net_volume_m3":0.141525,"object_name":"BIM3117_Wall003","quantity_rule":"3117.material.native-solid-partition.v1","thickness_m":0.015,"type_id":"65e313b7-786b-475f-994c-60b3af109888","type_name":"Wall 200 layered"},{"category":"Wall","content_revision":"b1d7558505e38e8eab14517490e580a875eba1bb7b5503b72d140c259384c804","deduction_rule":"openings","deduction_volume_m3":0.0,"element_id":"dbf814eb-5b9e-46d8-920e-1708f310fba8","gross_volume_m3":1.60395,"layer_index":2,"layer_role":"core","level":"L00","level_id":"4bd6b473-7294-4b93-b953-97c20a2378cf","material_code":"MASONRY","material_id":"09ac0651-dd5b-492a-845e-e1a702f0de0b","material_name":"Masonry","name":"Wall 1-4","net_volume_m3":1.60395,"object_name":"BIM3117_Wall003","quantity_rule":"3117.material.native-solid-partition.v1","thickness_m":0.17,"type_id":"65e313b7-786b-475f-994c-60b3af109888","type_name":"Wall 200 layered"},{"category":"Wall","content_revision":"b1d7558505e38e8eab14517490e580a875eba1bb7b5503b72d140c259384c804","deduction_rule":"openings","deduction_volume_m3":0.0,"element_id":"dbf814eb-5b9e-46d8-920e-1708f310fba8","gross_volume_m3":0.141525,"layer_index":3,"layer_role":"finish","level":"L00","level_id":"4bd6b473-7294-4b93-b953-97c20a2378cf","material_code":"PLASTER","material_id":"52f257eb-2c99-4630-9ba8-4108f966e817","material_name":"Plaster","name":"Wall 1-4","net_volume_m3":0.141525,"object_name":"BIM3117_Wall003","quantity_rule":"3117.material.native-solid-partition.v1","thickness_m":0.015,"type_id":"65e313b7-786b-475f-994c-60b3af109888","type_name":"Wall 200 layered"}]
Wall 1-3 | L00 | BIM3117_Wall002 | 5.7 | 14.535 | 14.535 | 2.907 | 2.907 | 0.218025 | 0 | 0.218025 | 2.47095 | 0 | 2.47095 | [{"category":"Wall","content_revision":"b1d7558505e38e8eab14517490e580a875eba1bb7b5503b72d140c259384c804","deduction_rule":"openings","deduction_volume_m3":0.0,"element_id":"e237c333-fb68-41bd-8547-c3d3517ec70f","gross_volume_m3":0.218025,"layer_index":1,"layer_role":"finish","level":"L00","level_id":"4bd6b473-7294-4b93-b953-97c20a2378cf","material_code":"PLASTER","material_id":"52f257eb-2c99-4630-9ba8-4108f966e817","material_name":"Plaster","name":"Wall 1-3","net_volume_m3":0.218025,"object_name":"BIM3117_Wall002","quantity_rule":"3117.material.native-solid-partition.v1","thickness_m":0.015,"type_id":"65e313b7-786b-475f-994c-60b3af109888","type_name":"Wall 200 layered"},{"category":"Wall","content_revision":"b1d7558505e38e8eab14517490e580a875eba1bb7b5503b72d140c259384c804","deduction_rule":"openings","deduction_volume_m3":0.0,"element_id":"e237c333-fb68-41bd-8547-c3d3517ec70f","gross_volume_m3":2.47095,"layer_index":2,"layer_role":"core","level":"L00","level_id":"4bd6b473-7294-4b93-b953-97c20a2378cf","material_code":"MASONRY","material_id":"09ac0651-dd5b-492a-845e-e1a702f0de0b","material_name":"Masonry","name":"Wall 1-3","net_volume_m3":2.47095,"object_name":"BIM3117_Wall002","quantity_rule":"3117.material.native-solid-partition.v1","thickness_m":0.17,"type_id":"65e313b7-786b-475f-994c-60b3af109888","type_name":"Wall 200 layered"},{"category":"Wall","content_revision":"b1d7558505e38e8eab14517490e580a875eba1bb7b5503b72d140c259384c804","deduction_rule":"openings","deduction_volume_m3":0.0,"element_id":"e237c333-fb68-41bd-8547-c3d3517ec70f","gross_volume_m3":0.218025,"layer_index":3,"layer_role":"finish","level":"L00","level_id":"4bd6b473-7294-4b93-b953-97c20a2378cf","material_code":"PLASTER","material_id":"52f257eb-2c99-4630-9ba8-4108f966e817","material_name":"Plaster","name":"Wall 1-3","net_volume_m3":0.218025,"object_name":"BIM3117_Wall002","quantity_rule":"3117.material.native-solid-partition.v1","thickness_m":0.015,"type_id":"65e313b7-786b-475f-994c-60b3af109888","type_name":"Wall 200 layered"}]
Wall 2-4 | L01 | BIM3117_Wall007 | 3.7 | 9.435 | 9.435 | 1.887 | 1.887 | 0.141525 | 0 | 0.141525 | 1.60395 | 0 | 1.60395 | [{"category":"Wall","content_revision":"b1d7558505e38e8eab14517490e580a875eba1bb7b5503b72d140c259384c804","deduction_rule":"openings","deduction_volume_m3":0.0,"element_id":"f2cae468-6358-471b-8a67-a9ed151a8112","gross_volume_m3":0.141525,"layer_index":1,"layer_role":"finish","level":"L01","level_id":"3087830e-4d1a-4f80-b674-777b13466c13","material_code":"PLASTER","material_id":"52f257eb-2c99-4630-9ba8-4108f966e817","material_name":"Plaster","name":"Wall 2-4","net_volume_m3":0.141525,"object_name":"BIM3117_Wall007","quantity_rule":"3117.material.native-solid-partition.v1","thickness_m":0.015,"type_id":"65e313b7-786b-475f-994c-60b3af109888","type_name":"Wall 200 layered"},{"category":"Wall","content_revision":"b1d7558505e38e8eab14517490e580a875eba1bb7b5503b72d140c259384c804","deduction_rule":"openings","deduction_volume_m3":0.0,"element_id":"f2cae468-6358-471b-8a67-a9ed151a8112","gross_volume_m3":1.60395,"layer_index":2,"layer_role":"core","level":"L01","level_id":"3087830e-4d1a-4f80-b674-777b13466c13","material_code":"MASONRY","material_id":"09ac0651-dd5b-492a-845e-e1a702f0de0b","material_name":"Masonry","name":"Wall 2-4","net_volume_m3":1.60395,"object_name":"BIM3117_Wall007","quantity_rule":"3117.material.native-solid-partition.v1","thickness_m":0.17,"type_id":"65e313b7-786b-475f-994c-60b3af109888","type_name":"Wall 200 layered"},{"category":"Wall","content_revision":"b1d7558505e38e8eab14517490e580a875eba1bb7b5503b72d140c259384c804","deduction_rule":"openings","deduction_volume_m3":0.0,"element_id":"f2cae468-6358-471b-8a67-a9ed151a8112","gross_volume_m3":0.141525,"layer_index":3,"layer_role":"finish","level":"L01","level_id":"3087830e-4d1a-4f80-b674-777b13466c13","material_code":"PLASTER","material_id":"52f257eb-2c99-4630-9ba8-4108f966e817","material_name":"Plaster","name":"Wall 2-4","net_volume_m3":0.141525,"object_name":"BIM3117_Wall007","quantity_rule":"3117.material.native-solid-partition.v1","thickness_m":0.015,"type_id":"65e313b7-786b-475f-994c-60b3af109888","type_name":"Wall 200 layered"}]

# IfcWindow: Window 1200 x 1200 (4)
Type - PredefinedType: WINDOW; ParameterTakesPrecedence: no; Material: Aluminium frame
Type - BIM3117_Source - ContentRevision: b1d7558505e38e8eab14517490e580a875eba1bb7b5503b72d140c259384c804; NativeObjectName: BIM3117_ElementType004; SourceModel: FreeCAD Document / FCStd; WorkbenchVersion: 0.5.0; TypeCode: WN1212; Category: Window; MaterialLayers: []; WidthM: 1.2; HeightM: 1.2; DimensionMeaning: Overall wall-cut opening including generic frame; no leaf, glazing or clear passage specification
OverallHeight: 1.2 m; OverallWidth: 1.2 m
BIM3117_Source - SillM: 0.9; Geometry: Generic four-bar window frame, no pane/leaf/operation; DimensionMeaning: Overall wall-cut opening including frame; not clear passage or leaf; FrameVolumeM3: 0.046
BIM3117_MaterialQuantities - HomogeneousGrossVolume: 0.046 m3; HomogeneousDeductionVolume: 0 m3; HomogeneousNetVolume: 0.046 m3
BIM3117_MaterialSource - ContentRevision: b1d7558505e38e8eab14517490e580a875eba1bb7b5503b72d140c259384c804; QuantityRule: 3117.material.native-solid-partition.v1
Name | In | NativeObjectName | OffsetM | Rows
WIN22 | L01 | BIM3117_Window003 | 1.2 | [{"category":"Window","content_revision":"b1d7558505e38e8eab14517490e580a875eba1bb7b5503b72d140c259384c804","deduction_rule":"none; generic frame solid, not the wall opening","deduction_volume_m3":0.0,"element_id":"13dab521-9139-425c-b8e7-c6df71ef7471","gross_volume_m3":0.045999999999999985,"layer_index":0,"layer_role":"homogeneous","level":"L01","level_id":"3087830e-4d1a-4f80-b674-777b13466c13","material_code":"ALU","material_id":"4e0d48ac-a10c-4dcd-9bb2-4adeb1a1c2eb","material_name":"Aluminium frame","name":"WIN22","net_volume_m3":0.045999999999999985,"object_name":"BIM3117_Window003","quantity_rule":"3117.material.native-solid-partition.v1","thickness_m":"","type_id":"cbfc4769-db95-4e84-a058-b6dce6456c61","type_name":"Window 1200 x 1200"}]
WIN21 | L01 | BIM3117_Window002 | 3 | [{"category":"Window","content_revision":"b1d7558505e38e8eab14517490e580a875eba1bb7b5503b72d140c259384c804","deduction_rule":"none; generic frame solid, not the wall opening","deduction_volume_m3":0.0,"element_id":"6448f086-9c0f-48c6-b97b-a62bb7ea2b74","gross_volume_m3":0.046,"layer_index":0,"layer_role":"homogeneous","level":"L01","level_id":"3087830e-4d1a-4f80-b674-777b13466c13","material_code":"ALU","material_id":"4e0d48ac-a10c-4dcd-9bb2-4adeb1a1c2eb","material_name":"Aluminium frame","name":"WIN21","net_volume_m3":0.046,"object_name":"BIM3117_Window002","quantity_rule":"3117.material.native-solid-partition.v1","thickness_m":"","type_id":"cbfc4769-db95-4e84-a058-b6dce6456c61","type_name":"Window 1200 x 1200"}]
WIN12 | L00 | BIM3117_Window001 | 1.2 | [{"category":"Window","content_revision":"b1d7558505e38e8eab14517490e580a875eba1bb7b5503b72d140c259384c804","deduction_rule":"none; generic frame solid, not the wall opening","deduction_volume_m3":0.0,"element_id":"83fb60f1-b5b2-4825-b529-5fd01ccff965","gross_volume_m3":0.045999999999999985,"layer_index":0,"layer_role":"homogeneous","level":"L00","level_id":"4bd6b473-7294-4b93-b953-97c20a2378cf","material_code":"ALU","material_id":"4e0d48ac-a10c-4dcd-9bb2-4adeb1a1c2eb","material_name":"Aluminium frame","name":"WIN12","net_volume_m3":0.045999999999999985,"object_name":"BIM3117_Window001","quantity_rule":"3117.material.native-solid-partition.v1","thickness_m":"","type_id":"cbfc4769-db95-4e84-a058-b6dce6456c61","type_name":"Window 1200 x 1200"}]
WIN11 | L00 | BIM3117_Window | 3 | [{"category":"Window","content_revision":"b1d7558505e38e8eab14517490e580a875eba1bb7b5503b72d140c259384c804","deduction_rule":"none; generic frame solid, not the wall opening","deduction_volume_m3":0.0,"element_id":"e63bc2ca-050e-4766-9aec-e07042fa5986","gross_volume_m3":0.046,"layer_index":0,"layer_role":"homogeneous","level":"L00","level_id":"4bd6b473-7294-4b93-b953-97c20a2378cf","material_code":"ALU","material_id":"4e0d48ac-a10c-4dcd-9bb2-4adeb1a1c2eb","material_name":"Aluminium frame","name":"WIN11","net_volume_m3":0.046,"object_name":"BIM3117_Window","quantity_rule":"3117.material.native-solid-partition.v1","thickness_m":"","type_id":"cbfc4769-db95-4e84-a058-b6dce6456c61","type_name":"Window 1200 x 1200"}]

# Material: Masonry
BIM3117_Source - Code: MASONRY; ContentRevision: b1d7558505e38e8eab14517490e580a875eba1bb7b5503b72d140c259384c804; NativeObjectName: BIM3117_Material001; SourceModel: FreeCAD Document / FCStd

# Material: Floor finish
BIM3117_Source - Code: FINISH; ContentRevision: b1d7558505e38e8eab14517490e580a875eba1bb7b5503b72d140c259384c804; NativeObjectName: BIM3117_Material003; SourceModel: FreeCAD Document / FCStd

# Material: Screed
BIM3117_Source - Code: SCREED; ContentRevision: b1d7558505e38e8eab14517490e580a875eba1bb7b5503b72d140c259384c804; NativeObjectName: BIM3117_Material004; SourceModel: FreeCAD Document / FCStd

# Material: Aluminium frame
BIM3117_Source - Code: ALU; ContentRevision: b1d7558505e38e8eab14517490e580a875eba1bb7b5503b72d140c259384c804; NativeObjectName: BIM3117_Material006; SourceModel: FreeCAD Document / FCStd

# Material: Plaster
BIM3117_Source - Code: PLASTER; ContentRevision: b1d7558505e38e8eab14517490e580a875eba1bb7b5503b72d140c259384c804; NativeObjectName: BIM3117_Material002; SourceModel: FreeCAD Document / FCStd

# Material: Timber frame
BIM3117_Source - Code: TIMBER; ContentRevision: b1d7558505e38e8eab14517490e580a875eba1bb7b5503b72d140c259384c804; NativeObjectName: BIM3117_Material005; SourceModel: FreeCAD Document / FCStd

# Material: Concrete
BIM3117_Source - Code: CONC; ContentRevision: b1d7558505e38e8eab14517490e580a875eba1bb7b5503b72d140c259384c804; NativeObjectName: BIM3117_Material; SourceModel: FreeCAD Document / FCStd
